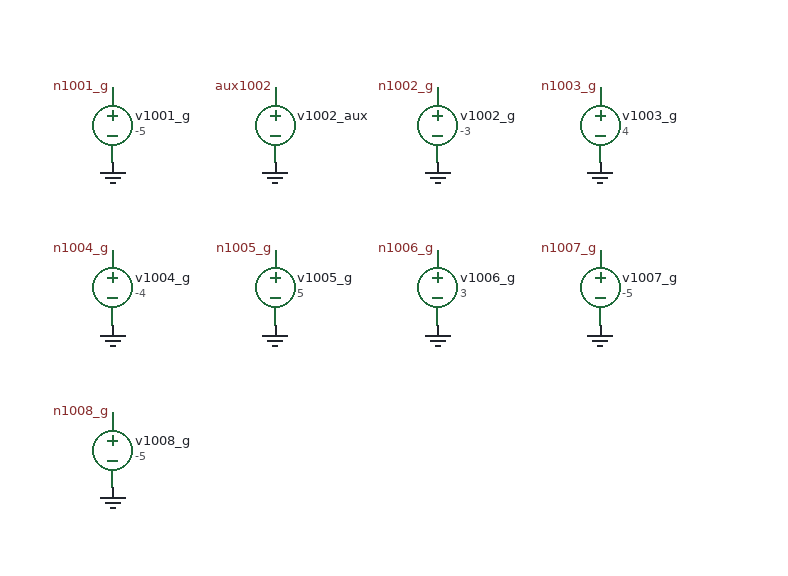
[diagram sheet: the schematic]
v {xschem version=3.4.5 file_version=1.2}
G {}
K {}
V {}
S {}
E {}
C {devices/vsource.sym} 300 150 0 0 {name=v1001_g
value=-5}
C {devices/vsource.sym} 430 150 0 0 {name=v1002_aux}
C {devices/vsource.sym} 560 150 0 0 {name=v1002_g
value=-3}
C {devices/vsource.sym} 690 150 0 0 {name=v1003_g
value=4}
C {devices/vsource.sym} 300 280 0 0 {name=v1004_g
value=-4}
C {devices/vsource.sym} 430 280 0 0 {name=v1005_g
value=5}
C {devices/vsource.sym} 560 280 0 0 {name=v1006_g
value=3}
C {devices/vsource.sym} 690 280 0 0 {name=v1007_g
value=-5}
C {devices/vsource.sym} 300 410 0 0 {name=v1008_g
value=-5}
C {devices/lab_pin.sym} 300 120 0 0 {name=l_n1001_g sig_type=std_logic lab=n1001_g}
C {devices/gnd.sym} 300 180 0 0 {name=l_0 lab=GND}
C {devices/gnd.sym} 430 180 0 0 {name=l_0 lab=GND}
C {devices/gnd.sym} 560 180 0 0 {name=l_0 lab=GND}
C {devices/gnd.sym} 690 180 0 0 {name=l_0 lab=GND}
C {devices/gnd.sym} 300 310 0 0 {name=l_0 lab=GND}
C {devices/gnd.sym} 430 310 0 0 {name=l_0 lab=GND}
C {devices/gnd.sym} 560 310 0 0 {name=l_0 lab=GND}
C {devices/gnd.sym} 690 310 0 0 {name=l_0 lab=GND}
C {devices/gnd.sym} 300 440 0 0 {name=l_0 lab=GND}
C {devices/lab_pin.sym} 430 120 0 0 {name=l_aux1002 sig_type=std_logic lab=aux1002}
C {devices/lab_pin.sym} 560 120 0 0 {name=l_n1002_g sig_type=std_logic lab=n1002_g}
C {devices/lab_pin.sym} 690 120 0 0 {name=l_n1003_g sig_type=std_logic lab=n1003_g}
C {devices/lab_pin.sym} 300 250 0 0 {name=l_n1004_g sig_type=std_logic lab=n1004_g}
C {devices/lab_pin.sym} 430 250 0 0 {name=l_n1005_g sig_type=std_logic lab=n1005_g}
C {devices/lab_pin.sym} 560 250 0 0 {name=l_n1006_g sig_type=std_logic lab=n1006_g}
C {devices/lab_pin.sym} 690 250 0 0 {name=l_n1007_g sig_type=std_logic lab=n1007_g}
C {devices/lab_pin.sym} 300 380 0 0 {name=l_n1008_g sig_type=std_logic lab=n1008_g}
